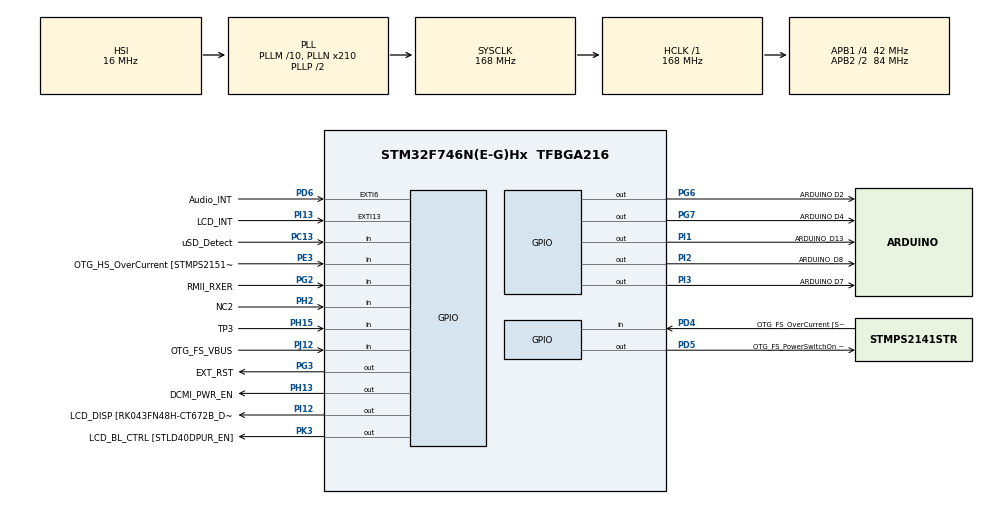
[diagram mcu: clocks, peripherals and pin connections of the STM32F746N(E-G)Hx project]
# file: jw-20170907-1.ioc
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Mcu.Family=STM32F7
Mcu.Name=STM32F746N(E-G)Hx
Mcu.Package=TFBGA216
NVIC.PriorityGroup=NVIC_PRIORITYGROUP_4
PA0/WKUP.GPIO_Label=ARDUINO A0
PA0/WKUP.GPIO_Mode=GPIO_MODE_ANALOG
PA0/WKUP.GPIO_PuPd=GPIO_NOPULL
PA0/WKUP.Signal=ADCx_IN0
PA1.GPIO_Label=RMII_REF_CLK [LAN8742A-CZ-TR_REFCLK0]
PA1.Signal=ETH_REF_CLK
PA10.GPIO_Label=OTG_FS_ID
PA10.Signal=USB_OTG_FS_ID
PA11.GPIO_Label=OTG_FS_N
PA11.Signal=USB_OTG_FS_DM
PA12.GPIO_Label=OTG_FS_P
PA12.Signal=USB_OTG_FS_DP
PA13.GPIO_Label=SWDIO
PA13.Signal=SYS_JTMS-SWDIO
PA14.GPIO_Label=SWCLK
PA14.Signal=SYS_JTCK-SWCLK
PA15.GPIO_Label=ARDUINO PWM/D9
PA15.GPIO_ModeDefaultPP=GPIO_MODE_AF_PP
PA15.GPIO_PuPd=GPIO_NOPULL
PA15.GPIO_Speed=GPIO_SPEED_FREQ_LOW
PA15.Signal=S_TIM2_CH1_ETR
PA2.GPIO_Label=RMII_MDIO [LAN8742A-CZ-TR_MDIO]
PA2.Signal=ETH_MDIO
PA3.GPIO_Label=ULPI_D0 [USB3320C-EZK_D0]
PA3.Signal=USB_OTG_HS_ULPI_D0
PA4.GPIO_Label=DCMI_HSYNC
PA4.Signal=DCMI_HSYNC
PA5.GPIO_Label=ULPI_CLK [USB3320C-EZK_CLKOUT]
PA5.Signal=USB_OTG_HS_ULPI_CK
PA6.Signal=DCMI_PIXCLK
PA7.GPIO_Label=RMII_CRS_DV [LAN8742A-CZ-TR_CRS_DV]
PA7.Signal=ETH_CRS_DV
PA8.GPIO_Label=ARDUINO PWM/D5
PA8.GPIO_ModeDefaultPP=GPIO_MODE_AF_PP
PA8.GPIO_PuPd=GPIO_NOPULL
PA8.GPIO_Speed=GPIO_SPEED_FREQ_LOW
PA8.Signal=S_TIM1_CH1
PB0.GPIO_Label=ULPI_D1 [USB3320C-EZK_D1]
PB0.Signal=USB_OTG_HS_ULPI_D1
PB1.GPIO_Label=ULPI_D2 [USB3320C-EZK_D2]
PB1.Signal=USB_OTG_HS_ULPI_D2
PB10.GPIO_Label=ULPI_D3 [USB3320C-EZK_D3]
PB10.Signal=USB_OTG_HS_ULPI_D3
PB11.GPIO_Label=ULPI_D4 [USB3320C-EZK_D4]
PB11.Signal=USB_OTG_HS_ULPI_D4
PB12.GPIO_Label=ULPI_D5 [USB3320C-EZK_D5]
PB12.Signal=USB_OTG_HS_ULPI_D5
PB13.GPIO_Label=ULPI_D6 [USB3320C-EZK_D6]
PB13.Signal=USB_OTG_HS_ULPI_D6
PB14.GPIO_Label=ARDUINO MISO/D12
PB14.GPIO_Mode=GPIO_MODE_AF_PP
PB14.GPIO_PuPd=GPIO_NOPULL
PB14.GPIO_Speed=GPIO_SPEED_FREQ_LOW
PB14.Signal=SPI2_MISO
PB15.GPIO_Label=ARDUINO MOSI/PWM/D11
PB15.GPIO_Mode=GPIO_MODE_AF_PP
PB15.GPIO_PuPd=GPIO_NOPULL
PB15.GPIO_Speed=GPIO_SPEED_FREQ_LOW
PB15.Signal=SPI2_MOSI
PB2.Signal=QUADSPI_CLK
PB3.GPIO_Label=SWO
PB3.Signal=SYS_JTDO-SWO
PB4.GPIO_Label=ARDUINO PWM/D3
PB4.GPIO_ModeDefaultPP=GPIO_MODE_AF_PP
PB4.GPIO_PuPd=GPIO_NOPULL
PB4.GPIO_Speed=GPIO_SPEED_FREQ_LOW
PB4.Signal=S_TIM3_CH1
PB5.GPIO_Label=ULPI_D7 [USB3320C-EZK_D7]
PB5.Signal=USB_OTG_HS_ULPI_D7
PB6.GPIO_Label=QSPI_NCS [N25Q128A13EF840E_S]
PB6.Signal=QUADSPI_BK1_NCS
PB7.GPIO_Label=VCP_RX [STM32F103CBT6_PA2]
PB7.GPIO_Mode=GPIO_MODE_AF_PP
PB7.GPIO_PuPd=GPIO_NOPULL
PB7.GPIO_Speed=GPIO_SPEED_FREQ_LOW
PB7.Signal=USART1_RX
PB8.GPIO_Label=ARDUINO SCL/D15
PB8.GPIO_Mode=GPIO_MODE_AF_OD
PB8.GPIO_PuPd=GPIO_NOPULL
PB8.GPIO_Speed=GPIO_SPEED_FREQ_LOW
PB8.Signal=I2C1_SCL
PB9.GPIO_Label=ARDUINO SDA/D14
PB9.GPIO_Mode=GPIO_MODE_AF_OD
PB9.GPIO_PuPd=GPIO_NOPULL
PB9.GPIO_Speed=GPIO_SPEED_FREQ_LOW
PB9.Signal=I2C1_SDA
PC0.GPIO_Label=ULPI_STP [USB3320C-EZK_STP]
PC0.Signal=USB_OTG_HS_ULPI_STP
PC1.GPIO_Label=RMII_MDC [LAN8742A-CZ-TR_MDC]
PC1.Signal=ETH_MDC
PC10.GPIO_Label=SDMMC_D2
PC10.Signal=SDMMC1_D2
PC11.GPIO_Label=SDMMC_D3
PC11.Signal=SDMMC1_D3
PC12.GPIO_Label=SDMMC_CK
PC12.Signal=SDMMC1_CK
PC13.GPIO_Label=uSD_Detect
PC13.Signal=GPIO_Input
PC14/OSC32_IN.GPIO_Label=RCC_OSC32_IN
PC14/OSC32_IN.Signal=RCC_OSC32_IN
PC15/OSC32_OUT.GPIO_Label=RCC_OSC32_OUT
PC15/OSC32_OUT.Signal=RCC_OSC32_OUT
PC2.GPIO_Label=ULPI_DIR [USB3320C-EZK_DIR]
PC2.Signal=USB_OTG_HS_ULPI_DIR
PC3.GPIO_Label=FMC_SDCKE0 [MT48LC4M32B2B5-6A_CKE]
PC3.Signal=FMC_SDCKE0
PC4.GPIO_Label=RMII_RXD0 [LAN8742A-CZ-TR_RXD0]
PC4.Signal=ETH_RXD0
PC5.GPIO_Label=RMII_RXD1 [LAN8742A-CZ-TR_RXD1]
PC5.Signal=ETH_RXD1
PC6.GPIO_Label=ARDUINO TX/D1
PC6.Signal=USART6_TX
PC7.GPIO_Label=ARDUINO RX/D0
PC7.Signal=USART6_RX
PC8.Signal=SDMMC1_D0
PC9.Signal=SDMMC1_D1
PD0.GPIO_Label=FMC_D2 [MT48LC4M32B2B5-6A_DQ2]
PD0.Signal=FMC_D2_DA2
PD1.GPIO_Label=FMC_D3 [MT48LC4M32B2B5-6A_DQ3]
PD1.Signal=FMC_D3_DA3
PD10.GPIO_Label=FMC_D15 [MT48LC4M32B2B5-6A_DQ15]
PD10.Signal=FMC_D15_DA15
PD11.GPIO_Label=QSPI_D0 [N25Q128A13EF840E_DQ0]
PD11.Signal=QUADSPI_BK1_IO0
PD12.GPIO_Label=QSPI_D1 [N25Q128A13EF840E_DQ1]
PD12.Signal=QUADSPI_BK1_IO1
PD13.GPIO_Label=QSPI_D3 [N25Q128A13EF840E_DQ3]
PD13.Signal=QUADSPI_BK1_IO3
PD14.GPIO_Label=FMC_D0 [MT48LC4M32B2B5-6A_DQ0]
PD14.Signal=FMC_D0_DA0
PD15.GPIO_Label=FMC_D1 [MT48LC4M32B2B5-6A_DQ1]
PD15.Signal=FMC_D1_DA1
PD2.GPIO_Label=SDMMC_D0
PD2.Signal=SDMMC1_CMD
PD3.GPIO_Label=DCMI_D5
PD3.Signal=DCMI_D5
PD4.GPIO_Label=OTG_FS_OverCurrent [STMPS2141STR_Fault]
PD4.Signal=GPIO_Input
PD5.GPIO_Label=OTG_FS_PowerSwitchOn [STMPS2141STR_EN]
PD5.PinState=GPIO_PIN_SET
PD5.Signal=GPIO_Output
PD6.GPIO_Label=Audio_INT
PD6.GPIO_ModeDefaultEXTI=GPIO_MODE_EVT_RISING
PD6.Signal=GPXTI6
PD7.GPIO_Label=SPDIF_RX0 [74LVC1G04SE_4]
PD7.Signal=SPDIFRX_IN0
PD8.GPIO_Label=FMC_D13 [MT48LC4M32B2B5-6A_DQ13]
PD8.Signal=FMC_D13_DA13
PD9.GPIO_Label=FMC_D14 [MT48LC4M32B2B5-6A_DQ14]
PD9.Signal=FMC_D14_DA14
PE0.GPIO_Label=FMC_NBL0 [MT48LC4M32B2B5-6A_DQM0]
PE0.Signal=FMC_NBL0
PE1.GPIO_Label=FMC_NBL1 [MT48LC4M32B2B5-6A_DQM1]
PE1.Signal=FMC_NBL1
PE10.GPIO_Label=FMC_D7 [MT48LC4M32B2B5-6A_DQ7]
PE10.Signal=FMC_D7_DA7
PE11.GPIO_Label=FMC_D8 [MT48LC4M32B2B5-6A_DQ8]
PE11.Signal=FMC_D8_DA8
PE12.GPIO_Label=FMC_D9 [MT48LC4M32B2B5-6A_DQ9]
PE12.Signal=FMC_D9_DA9
PE13.GPIO_Label=FMC_D10 [MT48LC4M32B2B5-6A_DQ10]
PE13.Signal=FMC_D10_DA10
PE14.GPIO_Label=FMC_D11 [MT48LC4M32B2B5-6A_DQ11]
PE14.Signal=FMC_D11_DA11
PE15.GPIO_Label=FMC_D12 [MT48LC4M32B2B5-6A_DQ12]
PE15.Signal=FMC_D12_DA12
PE2.GPIO_Label=QSPI_D2 [N25Q128A13EF840E_DQ2]
PE2.Signal=QUADSPI_BK1_IO2
PE3.GPIO_Label=OTG_HS_OverCurrent [STMPS2151STR_FAULT]
PE3.Signal=GPIO_Input
PE4.GPIO_Label=LCD_B0 [RK043FN48H-CT672B_B0]
PE4.Signal=LTDC_B0
PE5.GPIO_Label=DCMI_D6
PE5.Signal=DCMI_D6
PE6.GPIO_Label=DCMI_D7
PE6.Signal=DCMI_D7
PE7.GPIO_Label=FMC_D4 [MT48LC4M32B2B5-6A_DQ4]
PE7.Signal=FMC_D4_DA4
PE8.GPIO_Label=FMC_D5 [MT48LC4M32B2B5-6A_DQ5]
PE8.Signal=FMC_D5_DA5
PE9.GPIO_Label=FMC_D6 [MT48LC4M32B2B5-6A_DQ6]
PE9.Signal=FMC_D6_DA6
PF0.GPIO_Label=FMC_A0 [MT48LC4M32B2B5-6A_A0]
PF0.Signal=FMC_A0
PF1.GPIO_Label=FMC_A1 [MT48LC4M32B2B5-6A_A1]
PF1.Signal=FMC_A1
PF10.GPIO_Label=ARDUINO A1
PF10.GPIO_Mode=GPIO_MODE_ANALOG
PF10.GPIO_PuPd=GPIO_NOPULL
PF10.Signal=ADC3_IN8
PF11.GPIO_Label=FMC_SDNRAS [MT48LC4M32B2B5-6A_RAS]
PF11.Signal=FMC_SDNRAS
PF12.GPIO_Label=FMC_A6 [MT48LC4M32B2B5-6A_A6]
PF12.Signal=FMC_A6
PF13.GPIO_Label=FMC_A7 [MT48LC4M32B2B5-6A_A7]
PF13.Signal=FMC_A7
PF14.GPIO_Label=FMC_A8 [MT48LC4M32B2B5-6A_A8]
PF14.Signal=FMC_A8
PF15.GPIO_Label=FMC_A9 [MT48LC4M32B2B5-6A_A9]
PF15.Signal=FMC_A9
PF2.GPIO_Label=FMC_A2 [MT48LC4M32B2B5-6A_A2]
PF2.Signal=FMC_A2
PF3.GPIO_Label=FMC_A3 [MT48LC4M32B2B5-6A_A3]
PF3.Signal=FMC_A3
PF4.GPIO_Label=FMC_A4 [MT48LC4M32B2B5-6A_A4]
PF4.Signal=FMC_A4
PF5.GPIO_Label=FMC_A5 [MT48LC4M32B2B5-6A_A5]
PF5.Signal=FMC_A5
PF6.GPIO_Label=ARDUINO A5
PF6.GPIO_Mode=GPIO_MODE_ANALOG
PF6.GPIO_PuPd=GPIO_NOPULL
PF6.Signal=ADC3_IN4
PF7.GPIO_Label=ARDUINO A4
PF7.GPIO_Mode=GPIO_MODE_ANALOG
PF7.GPIO_PuPd=GPIO_NOPULL
PF7.Signal=ADC3_IN5
PF8.GPIO_Label=ARDUINO A3
PF8.GPIO_Mode=GPIO_MODE_ANALOG
PF8.GPIO_PuPd=GPIO_NOPULL
PF8.Signal=ADC3_IN6
PF9.GPIO_Label=ARDUINO A2
PF9.GPIO_Mode=GPIO_MODE_ANALOG
PF9.GPIO_PuPd=GPIO_NOPULL
PF9.Signal=ADC3_IN7
PG0.GPIO_Label=FMC_A10 [MT48LC4M32B2B5-6A_A10]
PG0.Signal=FMC_A10
PG1.GPIO_Label=FMC_A11 [MT48LC4M32B2B5-6A_A11]
PG1.Signal=FMC_A11
PG10.GPIO_Label=SAI2_SDB [WM8994ECS/R_ADCDAT1]
PG10.Signal=SAI2_SD_B
PG11.GPIO_Label=RMII_TX_EN [LAN8742A-CZ-TR_TXEN]
PG11.Signal=ETH_TX_EN
PG12.GPIO_Label=LCD_B4 [RK043FN48H-CT672B_B4]
PG12.Signal=LTDC_B4
PG13.GPIO_Label=RMII_TXD0 [LAN8742A-CZ-TR_TXD0]
PG13.Signal=ETH_TXD0
PG14.GPIO_Label=RMII_TXD1 [LAN8742A-CZ-TR_TXD1]
PG14.Signal=ETH_TXD1
PG15.GPIO_Label=FMC_SDNCAS [MT48LC4M32B2B5-6A_CAS]
PG15.Signal=FMC_SDNCAS
PG2.GPIO_Label=RMII_RXER
PG2.Signal=GPIO_Input
PG3.GPIO_Label=EXT_RST
PG3.Signal=GPIO_Output
PG4.GPIO_Label=FMC_BA0 [MT48LC4M32B2B5-6A_BA0]
PG4.Signal=FMC_A14_BA0
PG5.GPIO_Label=FMC_BA1 [MT48LC4M32B2B5-6A_BA1]
PG5.Signal=FMC_A15_BA1
PG6.GPIO_Label=ARDUINO D2
PG6.Signal=GPIO_Output
PG7.GPIO_Label=ARDUINO D4
PG7.Signal=GPIO_Output
PG8.GPIO_Label=FMC_SDCLK [MT48LC4M32B2B5-6A_CLK]
PG8.Signal=FMC_SDCLK
PG9.GPIO_Label=DCMI_VSYNC
PG9.Signal=DCMI_VSYNC
PH0/OSC_IN.GPIO_Label=OSC_25M [NZ2520SB-25.00M_OUT]
PH0/OSC_IN.Signal=RCC_OSC_IN
PH1/OSC_OUT.Signal=RCC_OSC_OUT
PH10.GPIO_Label=DCMI_D1
PH10.Signal=DCMI_D1
PH11.GPIO_Label=DCMI_D2
PH11.Signal=DCMI_D2
PH12.GPIO_Label=DCMI_D3
PH12.Signal=DCMI_D3
PH13.GPIO_Label=DCMI_PWR_EN
PH13.Signal=GPIO_Output
PH14.GPIO_Label=DCMI_D4
PH14.Signal=DCMI_D4
PH15.GPIO_Label=TP3
PH15.Signal=GPIO_Input
PH2.GPIO_Label=NC2
PH2.Signal=GPIO_Input
PH3.GPIO_Label=FMC_SDNE0 [MT48LC4M32B2B5-6A_CS]
PH3.Signal=FMC_SDNE0
PH4.GPIO_Label=ULPI_NXT [USB3320C-EZK_NXT]
PH4.Signal=USB_OTG_HS_ULPI_NXT
PH5.GPIO_Label=FMC_SDNME [MT48LC4M32B2B5-6A_WE]
PH5.Signal=FMC_SDNWE
PH6.GPIO_Label=ARDUINO PWM/D6
PH6.Signal=S_TIM12_CH1
PH7.GPIO_Label=LCD_SCL [RK043FN48H-CT672B_SCL]
PH7.Signal=I2C3_SCL
PH8.GPIO_Label=LCD_SDA [RK043FN48H-CT672B_SDA]
PH8.Signal=I2C3_SDA
PH9.GPIO_Label=DCMI_D0
PH9.Signal=DCMI_D0
PI0.GPIO_Label=ARDUINO PWM/CS/D10
PI0.GPIO_ModeDefaultPP=GPIO_MODE_AF_PP
PI0.GPIO_PuPd=GPIO_NOPULL
PI0.GPIO_Speed=GPIO_SPEED_FREQ_LOW
PI0.Signal=S_TIM5_CH4
PI1.GPIO_Label=ARDUINO_D13
PI1.Signal=GPIO_Output
PI10.GPIO_Label=LCD_HSYNC [RK043FN48H-CT672B_HSYNC]
PI10.Signal=LTDC_HSYNC
PI12.GPIO_Label=LCD_DISP [RK043FN48H-CT672B_DISP] 
PI12.Signal=GPIO_Output
PI13.GPIO_Label=LCD_INT
PI13.GPIO_ModeDefaultEXTI=GPIO_MODE_EVT_RISING
PI13.Signal=GPXTI13
PI14.GPIO_Label=LCD_CLK [RK043FN48H-CT672B_CLK]
PI14.Signal=LTDC_CLK
PI15.GPIO_Label=LCD_R0 [RK043FN48H-CT672B_R0]
PI15.Signal=LTDC_R0
PI2.GPIO_Label=ARDUINO_D8
PI2.Signal=GPIO_Output
PI3.GPIO_Label=ARDUINO D7
PI3.Signal=GPIO_Output
PI4.GPIO_Label=SAI2_MCLKA [WM8994ECS/R_MCLK1]
PI4.Signal=SAI2_MCLK_A
PI5.GPIO_Label=SAI2_SCKA [WM8994ECS/R_BCLK1]
PI5.Signal=SAI2_SCK_A
PI6.GPIO_Label=SAI2_SDA [WM8994ECS/R_DACDAT1]
PI6.Signal=SAI2_SD_A
PI7.GPIO_Label=SAI2_FSA [WM8994ECS/R_LRCLK1]
PI7.Signal=SAI2_FS_A
PI8.GPIO_Label=NC1 [TP2]
PI8.Signal=RTC_TS
PI9.GPIO_Label=LCD_VSYNC [RK043FN48H-CT672B_VSYNC]
PI9.Signal=LTDC_VSYNC
PJ0.GPIO_Label=LCD_R1 [RK043FN48H-CT672B_R1]
PJ0.Signal=LTDC_R1
PJ1.GPIO_Label=LCD_R2 [RK043FN48H-CT672B_R2]
PJ1.Signal=LTDC_R2
PJ10.GPIO_Label=LCD_G3 [RK043FN48H-CT672B_G3]
PJ10.Signal=LTDC_G3
PJ11.GPIO_Label=LCD_G4 [RK043FN48H-CT672B_G4]
PJ11.Signal=LTDC_G4
PJ12.GPIO_Label=OTG_FS_VBUS
PJ12.Signal=GPIO_Input
PJ13.GPIO_Label=LCD_B1 [RK043FN48H-CT672B_B1]
PJ13.Signal=LTDC_B1
PJ14.GPIO_Label=LCD_B2 [RK043FN48H-CT672B_B2]
PJ14.Signal=LTDC_B2
PJ15.GPIO_Label=LCD_B3 [RK043FN48H-CT672B_B3]
PJ15.Signal=LTDC_B3
PJ2.GPIO_Label=LCD_R3 [RK043FN48H-CT672B_R3]
PJ2.Signal=LTDC_R3
PJ3.GPIO_Label=LCD_R4 [RK043FN48H-CT672B_R4]
PJ3.Signal=LTDC_R4
PJ4.GPIO_Label=LCD_R5 [RK043FN48H-CT672B_R5]
PJ4.Signal=LTDC_R5
PJ5.GPIO_Label=LCD_R6 [RK043FN48H-CT672B_R6]
PJ5.Signal=LTDC_R6
PJ6.GPIO_Label=LCD_R7 [RK043FN48H-CT672B_R7]
PJ6.Signal=LTDC_R7
PJ7.GPIO_Label=LCD_G0 [RK043FN48H-CT672B_G0]
PJ7.Signal=LTDC_G0
PJ8.GPIO_Label=LCD_G1 [RK043FN48H-CT672B_G1]
PJ8.Signal=LTDC_G1
PJ9.GPIO_Label=LCD_G2 [RK043FN48H-CT672B_G2]
PJ9.Signal=LTDC_G2
PK0.GPIO_Label=LCD_G5 [RK043FN48H-CT672B_G5]
PK0.Signal=LTDC_G5
PK1.GPIO_Label=LCD_G6 [RK043FN48H-CT672B_G6]
PK1.Signal=LTDC_G6
PK2.GPIO_Label=LCD_G7 [RK043FN48H-CT672B_G7]
PK2.Signal=LTDC_G7
PK3.GPIO_Label=LCD_BL_CTRL [STLD40DPUR_EN]
PK3.Signal=GPIO_Output
PK4.GPIO_Label=LCD_B5 [RK043FN48H-CT672B_B5]
PK4.Signal=LTDC_B5
PK5.GPIO_Label=LCD_B6 [RK043FN48H-CT672B_B6]
PK5.Signal=LTDC_B6
PK6.GPIO_Label=LCD_B7 [RK043FN48H-CT672B_B7]
PK6.Signal=LTDC_B7
PK7.GPIO_Label=LCD_DE [RK043FN48H-CT672B_DE]
PK7.Signal=LTDC_DE
ProjectManager.HeapSize=0x200
ProjectManager.StackSize=0x400
ProjectManager.TargetToolchain=EWARM
RCC.AHBFreq_Value=168000000
RCC.APB1CLKDivider=RCC_HCLK_DIV4
RCC.APB1Freq_Value=42000000
RCC.APB1TimFreq_Value=84000000
RCC.APB2CLKDivider=RCC_HCLK_DIV2
RCC.APB2Freq_Value=84000000
RCC.APB2TimFreq_Value=168000000
RCC.CortexFreq_Value=168000000
RCC.HCLKFreq_Value=168000000
RCC.HSE_VALUE=25000000
RCC.HSI_VALUE=16000000
RCC.LSE_VALUE=32768
RCC.PLLM=10
RCC.PLLN=210
RCC.PLLSourceVirtual=RCC_PLLSOURCE_HSI
RCC.SYSCLKFreq_VALUE=168000000
RCC.SYSCLKSource=RCC_SYSCLKSOURCE_PLLCLK
RCC.USBFreq_Value=168000000
RCC.VCOOutputFreq_Value=336000000
SH.ADCx_IN0.0=ADC3_IN0
SH.FMC_A0.0=FMC_A0
SH.FMC_A1.0=FMC_A1
SH.FMC_A10.0=FMC_A10
SH.FMC_A11.0=FMC_A11
SH.FMC_A14_BA0.0=FMC_BA0
SH.FMC_A15_BA1.0=FMC_BA1
SH.FMC_A2.0=FMC_A2
SH.FMC_A3.0=FMC_A3
SH.FMC_A4.0=FMC_A4
SH.FMC_A5.0=FMC_A5
SH.FMC_A6.0=FMC_A6
SH.FMC_A7.0=FMC_A7
SH.FMC_A8.0=FMC_A8
SH.FMC_A9.0=FMC_A9
SH.FMC_D0_DA0.0=FMC_D0
SH.FMC_D10_DA10.0=FMC_D10
SH.FMC_D11_DA11.0=FMC_D11
SH.FMC_D12_DA12.0=FMC_D12
SH.FMC_D13_DA13.0=FMC_D13
SH.FMC_D14_DA14.0=FMC_D14
SH.FMC_D15_DA15.0=FMC_D15
SH.FMC_D1_DA1.0=FMC_D1
SH.FMC_D2_DA2.0=FMC_D2
SH.FMC_D3_DA3.0=FMC_D3
SH.FMC_D4_DA4.0=FMC_D4
SH.FMC_D5_DA5.0=FMC_D5
SH.FMC_D6_DA6.0=FMC_D6
SH.FMC_D7_DA7.0=FMC_D7
SH.FMC_D8_DA8.0=FMC_D8
SH.FMC_D9_DA9.0=FMC_D9
SH.FMC_NBL0.0=FMC_NBL0
SH.FMC_NBL1.0=FMC_NBL1
SH.FMC_SDCLK.0=FMC_SDCLK
SH.FMC_SDNCAS.0=FMC_SDNCAS
SH.FMC_SDNRAS.0=FMC_SDNRAS
SH.FMC_SDNWE.0=FMC_SDNWE
SH.S_TIM12_CH1.0=TIM12_CH1
SH.S_TIM1_CH1.0=TIM1_CH1
SH.S_TIM2_CH1_ETR.0=TIM2_CH1
SH.S_TIM3_CH1.0=TIM3_CH1
SH.S_TIM5_CH4.0=TIM5_CH4
board=STM32F746G-DISCO

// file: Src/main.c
/**
  ******************************************************************************
  * File Name          : main.c
  * Description        : Main program body
  ******************************************************************************
  ** This notice applies to any and all portions of this file
  * that are not between comment pairs USER CODE BEGIN and
  * USER CODE END. Other portions of this file, whether
  * inserted by the user or by software development tools
  * are owned by their respective copyright owners.
  *
  * COPYRIGHT(c) 2017 STMicroelectronics
  *
  * Redistribution and use in source and binary forms, with or without modification,
  * are permitted provided that the following conditions are met:
  *   1. Redistributions of source code must retain the above copyright notice,
  *      this list of conditions and the following disclaimer.
  *   2. Redistributions in binary form must reproduce the above copyright notice,
  *      this list of conditions and the following disclaimer in the documentation
  *      and/or other materials provided with the distribution.
  *   3. Neither the name of STMicroelectronics nor the names of its contributors
  *      may be used to endorse or promote products derived from this software
  *      without specific prior written permission.
  *
  * THIS SOFTWARE IS PROVIDED BY THE COPYRIGHT HOLDERS AND CONTRIBUTORS "AS IS"
  * AND ANY EXPRESS OR IMPLIED WARRANTIES, INCLUDING, BUT NOT LIMITED TO, THE
  * IMPLIED WARRANTIES OF MERCHANTABILITY AND FITNESS FOR A PARTICULAR PURPOSE ARE
  * DISCLAIMED. IN NO EVENT SHALL THE COPYRIGHT HOLDER OR CONTRIBUTORS BE LIABLE
  * FOR ANY DIRECT, INDIRECT, INCIDENTAL, SPECIAL, EXEMPLARY, OR CONSEQUENTIAL
  * DAMAGES (INCLUDING, BUT NOT LIMITED TO, PROCUREMENT OF SUBSTITUTE GOODS OR
  * SERVICES; LOSS OF USE, DATA, OR PROFITS; OR BUSINESS INTERRUPTION) HOWEVER
  * CAUSED AND ON ANY THEORY OF LIABILITY, WHETHER IN CONTRACT, STRICT LIABILITY,
  * OR TORT (INCLUDING NEGLIGENCE OR OTHERWISE) ARISING IN ANY WAY OUT OF THE USE
  * OF THIS SOFTWARE, EVEN IF ADVISED OF THE POSSIBILITY OF SUCH DAMAGE.
  *
  ******************************************************************************
  */
#include "main.h"
#include "stm32f7xx_hal.h"
#include "main_FSM.h"

/*
This code Written By DDubi(jw8704@gmail.com).
Date : 2017.09.18
Coaching from Firmware enginner's talk chatroom's master
*/

//This Conidtion is optional. (written by DDubi(kim jinwoo)
#define USING_DELAY_VER

//Only one condition must be specified.(written by DDubi(kim jinwoo)
//#define USING_QUEUE
#define USING_FLAG

//CAUTION!!! Do not Remove or Modify (Written By DDubi(kim jinwoo)---->
#if defined(USING_FLAG) && defined (USING_QUEUE)
CAUTION! Both conditions can not exist at the same time.
#endif
#if !defined(USING_FLAG) && !defined (USING_QUEUE)
CAUTION! One of the two conditions must be specified.
#endif
//<------Caution!! Do not Remove or Modify(Written By DDubi(kim jinwoo)

/* USER CODE BEGIN PV */
/* Private variables ---------------------------------------------------------*/

/* USER CODE END PV */

void SystemClock_Config(void);
static void MX_GPIO_Init(void);
typedef int element;

extern void enqueue(int *rear,element item);
extern int isEmpty(int *front,int rear);
extern element dequeue(int *front,int rear);
extern void deleteitem(int *front,int rear);
extern element peek(int front,int rear);

/* USER CODE BEGIN PFP */
/* Private function prototypes -----------------------------------------------*/

/* USER CODE END PFP */

int ledstate=0;

#ifdef USING_FLAG
int updateEvent=0;
#endif

 //FSM_EVT e;
 //FSM     f;
  FSM_EVT e;
 FSM     f;

 int front = -1;
 int rear = -1;

void HAL_GPIO_EXTI_Callback(uint16_t GPIO_Pin)
{

 /*
  if(ledstate==0)
  {
   InitStateMachine(
        &f,                  // 초기화할 FSM 개체(개수만큼 생성 초기화해준다)
        InitMainFSM(&f),     // MainFSM 초기화함수(FSM 마다 만들어 준다) : 상태테이블 리턴
        _MOVEMAN_MAX_EVT,    // 이벤트 개수
        _MOVEMAN_MAX_STATE   // STATE  개수
    );
   ledstate=9;
  }*/
  //else
 // {
  // __HAL_GPIO_EXTI_CLEAR_IT(GPIO_PIN_11);
 // UNUSED(GPIO_PIN_11);
 // asm("NOP");
//
                if(GetState(f)==_MOVEMAN_LEVEL_1)
                {
                  asm("NOP");
                    e.EVT = _MOVEMAN_GO_UP;   //DoEvent(&f, e);
#ifdef USING_QUEUE
                    enqueue(&rear,e.EVT);
#endif
                     asm("NOP");
                  //  asm("NOP");
                   // UNUSED(GPIO_PIN_11);
#ifdef USING_FLAG
                     updateEvent=1;
#endif
                }

                else if(GetState(f)==_MOVEMAN_LEVEL_2)
               {
                 asm("NOP");

                 e.EVT = _MOVEMAN_GO_DOWN; //DoEvent(&f, e);
#ifdef USING_QUEUE
                 enqueue(&rear,e.EVT);
#endif
                  asm("NOP");
#ifdef USING_FLAG
                  updateEvent=1;
#endif
               }
 // }
               //  asm("NOP");
            // UNUSED(GPIO_PIN_11);
              // }
           //asm("NOP");

  //HAL_GPIO_TogglePin(LCD_BK_CTRL_GPIO_Port, LCD_BK_CTRL_Pin);

  /*
  if(ledstate==0)
                {
                HAL_GPIO_WritePin(GPIOI,ARDUINO_D7_Pin,GPIO_PIN_RESET);
                HAL_GPIO_WritePin(GPIOI,ARDUINO_D8_Pin,GPIO_PIN_RESET);
                HAL_GPIO_TogglePin(GPIOI,ARDUINO_D7_Pin);
                ledstate=1;
                //HAL_Delay(180);
                printf("test\n");
                }
                else if(ledstate==1)
                {
                HAL_GPIO_WritePin(GPIOI,ARDUINO_D7_Pin,GPIO_PIN_RESET);
                HAL_GPIO_WritePin(GPIOI,ARDUINO_D8_Pin,GPIO_PIN_RESET);
                HAL_GPIO_TogglePin(GPIOI,ARDUINO_D8_Pin);
                ledstate=0;
                //HAL_Delay(180);
                }*/
  //UNUSED(GPIO_PIN_11);
          // __HAL_GPIO_EXTI_CLEAR_IT(GPIO_PIN_11);
}

int main(void)
{

 //FSM_EVT e;
 //  FSM     f;

  /* USER CODE BEGIN 1 */

    // StateMachine 초기화

    InitStateMachine(
        &f,                  // 초기화할 FSM 개체(개수만큼 생성 초기화해준다)
        InitMainFSM(&f),     // MainFSM 초기화함수(FSM 마다 만들어 준다) : 상태테이블 리턴
        _MOVEMAN_MAX_EVT,    // 이벤트 개수
        _MOVEMAN_MAX_STATE   // STATE  개수
    );

  /* USER CODE END 1 */

  /* MCU Configuration----------------------------------------------------------*/

  /* Reset of all peripherals, Initializes the Flash interface and the Systick. */
  HAL_Init();

  /* Configure the system clock */
  SystemClock_Config();

  /* Initialize all configured peripherals */
  MX_GPIO_Init();

  /* Infinite loop */
  /* USER CODE BEGIN WHILE */

  //RCC->AHB1ENR |= 0x00000100;  // GPIOI clock enable
  //GPIOI->MODER = 0x00000008;   // PI1 (LED) output

//  uint8_t sw_in,sw_in_old,f_test=0;
 // sw_in = sw_in_old = HAL_GPIO_ReadPin(SW_IN_GPIO_Port,SW_IN_Pin);

 //int ledstate;

 //ledstate=0;
  //MX_USART1_UART_Init();

 while (1)
  {
  /* USER CODE END WHILE */
//delay(1000);
#ifdef USING_DELAY_VER
  HAL_Delay(1000);
#endif

#ifdef USING_QUEUE
  if(front!=rear)
#endif
#ifdef USING_FLAG
   if(updateEvent)
#endif
    {
#ifdef USING_QUEUE
    if(peek(front,rear) == _MOVEMAN_GO_UP)
#endif
#ifdef USING_FLAG
      if(e.EVT == _MOVEMAN_GO_UP)
#endif
                {
                  asm("NOP");
                    //e.EVT = _MOVEMAN_GO_UP;
                  DoEvent(&f, e);
                     asm("NOP");
                  //  asm("NOP");
                   // UNUSED(GPIO_PIN_11);
                }
#ifdef USING_QUEUE
    else if(peek(front,rear) == _MOVEMAN_GO_DOWN)
#endif
#ifdef USING_FLAG
     else if(e.EVT == _MOVEMAN_GO_DOWN)
#endif
               {
                 asm("NOP");

                 //e.EVT = _MOVEMAN_GO_DOWN;

                 DoEvent(&f, e);
                  asm("NOP");
               }
#ifdef USING_QUEUE
     dequeue(&front,rear);
#endif

#ifdef USING_FLAG
     updateEvent=0;
#endif
    }

  /* USER CODE BEGIN 3 */
 // HAL_GPIO_TogglePin(GPIOI,ARDUINO_D8_Pin);
  //HAL_Delay(1000);

        //    if (GPIOI->IDR & 0x0800) // Input state of PI11 (switch)
       //     {
                     //GPIOI->BSRR = 0x00000002;  // Set PI1
                // HAL_GPIO_TogglePin(GPIOI,ARDUINO_D8_Pin);
                // HAL_GPIO_TogglePin(GPIOI,ARDUINO_D8_Pin);
               /*
              if(GetState(f)==_MOVEMAN_LEVEL_1)
                {
                    e.EVT = _MOVEMAN_GO_UP;    DoEvent(&f, e);
                }
                else if(GetState(f)==_MOVEMAN_LEVEL_2)
               {
                    e.EVT = _MOVEMAN_GO_DOWN;  DoEvent(&f, e);
               }

                 */
                 //HAL_Delay(1000);
           //  }
              /*
              else
              {
               // HAL_GPIO_TogglePin(GPIOI,ARDUINO_D7_Pin);
                HAL_GPIO_WritePin(GPIOI,ARDUINO_D7_Pin,GPIO_PIN_RESET);
                 HAL_GPIO_TogglePin(GPIOI,ARDUINO_D8_Pin);
                 //HAL_Delay(1000);
               // HAL_GPIO_TogglePin(GPIOI,ARDUINO_D8_Pin);
                     //GPIOI->BSRR = 0x00020000;  // Reset PI1
              }
              */
  }
}
  /* USER CODE END 3 */

/** System Clock Configuration
*/
void SystemClock_Config(void)
{

  RCC_OscInitTypeDef RCC_OscInitStruct;
  RCC_ClkInitTypeDef RCC_ClkInitStruct;

    /**Configure the main internal regulator output voltage
    */
  __HAL_RCC_PWR_CLK_ENABLE();

  __HAL_PWR_VOLTAGESCALING_CONFIG(PWR_REGULATOR_VOLTAGE_SCALE2);

    /**Initializes the CPU, AHB and APB busses clocks
    */
  RCC_OscInitStruct.OscillatorType = RCC_OSCILLATORTYPE_HSI;
  RCC_OscInitStruct.HSIState = RCC_HSI_ON;
  RCC_OscInitStruct.HSICalibrationValue = 16;
  RCC_OscInitStruct.PLL.PLLState = RCC_PLL_ON;
  RCC_OscInitStruct.PLL.PLLSource = RCC_PLLSOURCE_HSI;
  RCC_OscInitStruct.PLL.PLLM = 10;
  RCC_OscInitStruct.PLL.PLLN = 210;
  RCC_OscInitStruct.PLL.PLLP = RCC_PLLP_DIV2;
  RCC_OscInitStruct.PLL.PLLQ = 2;
  if (HAL_RCC_OscConfig(&RCC_OscInitStruct) != HAL_OK)
  {
    _Error_Handler(__FILE__, __LINE__);
  }

    /**Initializes the CPU, AHB and APB busses clocks
    */
  RCC_ClkInitStruct.ClockType = RCC_CLOCKTYPE_HCLK|RCC_CLOCKTYPE_SYSCLK
                              |RCC_CLOCKTYPE_PCLK1|RCC_CLOCKTYPE_PCLK2;
  RCC_ClkInitStruct.SYSCLKSource = RCC_SYSCLKSOURCE_PLLCLK;
  RCC_ClkInitStruct.AHBCLKDivider = RCC_SYSCLK_DIV1;
  RCC_ClkInitStruct.APB1CLKDivider = RCC_HCLK_DIV4;
  RCC_ClkInitStruct.APB2CLKDivider = RCC_HCLK_DIV2;

  if (HAL_RCC_ClockConfig(&RCC_ClkInitStruct, FLASH_LATENCY_5) != HAL_OK)
  {
    _Error_Handler(__FILE__, __LINE__);
  }

    /**Configure the Systick interrupt time
    */
  HAL_SYSTICK_Config(HAL_RCC_GetHCLKFreq()/1000);

    /**Configure the Systick
    */
  HAL_SYSTICK_CLKSourceConfig(SYSTICK_CLKSOURCE_HCLK);

  /* SysTick_IRQn interrupt configuration */
  HAL_NVIC_SetPriority(SysTick_IRQn, 0, 0);
}

/** Configure pins
     PE4   ------> LTDC_B0
     PE2   ------> QUADSPI_BK1_IO2
     PG14   ------> ETH_TXD1
     PE1   ------> FMC_NBL1
     PE0   ------> FMC_NBL0
     PB8   ------> I2C1_SCL
     PB5   ------> USB_OTG_HS_ULPI_D7
     PB4   ------> S_TIM3_CH1
     PD7   ------> SPDIFRX_IN0
     PC12   ------> SDMMC1_CK
     PA15   ------> S_TIM2_CH1_ETR
     PE5   ------> DCMI_D6
     PE6   ------> DCMI_D7
     PG13   ------> ETH_TXD0
     PB9   ------> I2C1_SDA
     PB7   ------> USART1_RX
     PB6   ------> QUADSPI_BK1_NCS
     PG15   ------> FMC_SDNCAS
     PG11   ------> ETH_TX_EN
     PJ13   ------> LTDC_B1
     PD0   ------> FMC_D2_DA2
     PC11   ------> SDMMC1_D3
     PC10   ------> SDMMC1_D2
     PA12   ------> USB_OTG_FS_DP
     PI4   ------> SAI2_MCLK_A
     PK7   ------> LTDC_DE
     PK6   ------> LTDC_B7
     PK5   ------> LTDC_B6
     PG12   ------> LTDC_B4
     PG10   ------> SAI2_SD_B
     PJ14   ------> LTDC_B2
     PD3   ------> DCMI_D5
     PD1   ------> FMC_D3_DA3
     PA11   ------> USB_OTG_FS_DM
     PF0   ------> FMC_A0
     PI5   ------> SAI2_SCK_A
     PI7   ------> SAI2_FS_A
     PI10   ------> LTDC_HSYNC
     PI6   ------> SAI2_SD_A
     PK4   ------> LTDC_B5
     PG9   ------> DCMI_VSYNC
     PJ15   ------> LTDC_B3
     PD2   ------> SDMMC1_CMD
     PA10   ------> USB_OTG_FS_ID
     PF1   ------> FMC_A1
     PI9   ------> LTDC_VSYNC
     PH14   ------> DCMI_D4
     PI0   ------> S_TIM5_CH4
     PK1   ------> LTDC_G6
     PK2   ------> LTDC_G7
     PC9   ------> SDMMC1_D1
     PA8   ------> S_TIM1_CH1
     PF2   ------> FMC_A2
     PI15   ------> LTDC_R0
     PJ11   ------> LTDC_G4
     PK0   ------> LTDC_G5
     PC8   ------> SDMMC1_D0
     PC7   ------> USART6_RX
     PF3   ------> FMC_A3
     PI14   ------> LTDC_CLK
     PH4   ------> USB_OTG_HS_ULPI_NXT
     PJ8   ------> LTDC_G1
     PJ10   ------> LTDC_G3
     PG8   ------> FMC_SDCLK
     PC6   ------> USART6_TX
     PF4   ------> FMC_A4
     PH5   ------> FMC_SDNWE
     PH3   ------> FMC_SDNE0
     PJ7   ------> LTDC_G0
     PJ9   ------> LTDC_G2
     PF7   ------> ADC3_IN5
     PF6   ------> ADC3_IN4
     PF5   ------> FMC_A5
     PJ6   ------> LTDC_R7
     PD15   ------> FMC_D1_DA1
     PB13   ------> USB_OTG_HS_ULPI_D6
     PD10   ------> FMC_D15_DA15
     PF10   ------> ADC3_IN8
     PF9   ------> ADC3_IN7
     PF8   ------> ADC3_IN6
     PC3   ------> FMC_SDCKE0
     PD14   ------> FMC_D0_DA0
     PB12   ------> USB_OTG_HS_ULPI_D5
     PD9   ------> FMC_D14_DA14
     PD8   ------> FMC_D13_DA13
     PC0   ------> USB_OTG_HS_ULPI_STP
     PC1   ------> ETH_MDC
     PC2   ------> USB_OTG_HS_ULPI_DIR
     PB2   ------> QUADSPI_CLK
     PF12   ------> FMC_A6
     PG1   ------> FMC_A11
     PF15   ------> FMC_A9
     PJ4   ------> LTDC_R5
     PD12   ------> QUADSPI_BK1_IO1
     PD13   ------> QUADSPI_BK1_IO3
     PJ5   ------> LTDC_R6
     PH12   ------> DCMI_D3
     PA1   ------> ETH_REF_CLK
     PA0/WKUP   ------> ADCx_IN0
     PA4   ------> DCMI_HSYNC
     PC4   ------> ETH_RXD0
     PF13   ------> FMC_A7
     PG0   ------> FMC_A10
     PJ3   ------> LTDC_R4
     PE8   ------> FMC_D5_DA5
     PD11   ------> QUADSPI_BK1_IO0
     PG5   ------> FMC_A15_BA1
     PG4   ------> FMC_A14_BA0
     PH7   ------> I2C3_SCL
     PH9   ------> DCMI_D0
     PH11   ------> DCMI_D2
     PA2   ------> ETH_MDIO
     PA6   ------> DCMI_PIXCLK
     PA5   ------> USB_OTG_HS_ULPI_CK
     PC5   ------> ETH_RXD1
     PF14   ------> FMC_A8
     PJ2   ------> LTDC_R3
     PF11   ------> FMC_SDNRAS
     PE9   ------> FMC_D6_DA6
     PE11   ------> FMC_D8_DA8
     PE14   ------> FMC_D11_DA11
     PB10   ------> USB_OTG_HS_ULPI_D3
     PH6   ------> S_TIM12_CH1
     PH8   ------> I2C3_SDA
     PH10   ------> DCMI_D1
     PA3   ------> USB_OTG_HS_ULPI_D0
     PA7   ------> ETH_CRS_DV
     PB1   ------> USB_OTG_HS_ULPI_D2
     PB0   ------> USB_OTG_HS_ULPI_D1
     PJ0   ------> LTDC_R1
     PJ1   ------> LTDC_R2
     PE7   ------> FMC_D4_DA4
     PE10   ------> FMC_D7_DA7
     PE12   ------> FMC_D9_DA9
     PE15   ------> FMC_D12_DA12
     PE13   ------> FMC_D10_DA10
     PB11   ------> USB_OTG_HS_ULPI_D4
     PB14   ------> SPI2_MISO
     PB15   ------> SPI2_MOSI
*/
static void MX_GPIO_Init(void)
{

  GPIO_InitTypeDef GPIO_InitStruct;

  /* GPIO Ports Clock Enable */
  __HAL_RCC_GPIOE_CLK_ENABLE();
  __HAL_RCC_GPIOG_CLK_ENABLE();
  __HAL_RCC_GPIOB_CLK_ENABLE();
  __HAL_RCC_GPIOD_CLK_ENABLE();
  __HAL_RCC_GPIOC_CLK_ENABLE();
  __HAL_RCC_GPIOA_CLK_ENABLE();
  __HAL_RCC_GPIOJ_CLK_ENABLE();
  __HAL_RCC_GPIOI_CLK_ENABLE();
  __HAL_RCC_GPIOK_CLK_ENABLE();
  __HAL_RCC_GPIOF_CLK_ENABLE();
  __HAL_RCC_GPIOH_CLK_ENABLE();

  /*Configure GPIO pin Output Level */
  HAL_GPIO_WritePin(OTG_FS_PowerSwitchOn_GPIO_Port, OTG_FS_PowerSwitchOn_Pin, GPIO_PIN_SET);

  /*Configure GPIO pin Output Level */
  HAL_GPIO_WritePin(GPIOI, ARDUINO_D7_Pin|ARDUINO_D8_Pin|LCD_DISP_Pin, GPIO_PIN_RESET);

  /*Configure GPIO pin Output Level */
  HAL_GPIO_WritePin(LCD_BL_CTRL_GPIO_Port, LCD_BL_CTRL_Pin, GPIO_PIN_RESET);

  /*Configure GPIO pin Output Level */
  HAL_GPIO_WritePin(DCMI_PWR_EN_GPIO_Port, DCMI_PWR_EN_Pin, GPIO_PIN_RESET);

  /*Configure GPIO pin Output Level */
  HAL_GPIO_WritePin(GPIOG, ARDUINO_D4_Pin|EXT_RST_Pin, GPIO_PIN_RESET);

  /*Configure GPIO pin : LCD_B0_Pin */
  GPIO_InitStruct.Pin = LCD_B0_Pin;
  GPIO_InitStruct.Mode = GPIO_MODE_AF_PP;
  GPIO_InitStruct.Pull = GPIO_NOPULL;
  GPIO_InitStruct.Speed = GPIO_SPEED_FREQ_LOW;
  GPIO_InitStruct.Alternate = GPIO_AF14_LTDC;
  HAL_GPIO_Init(LCD_B0_GPIO_Port, &GPIO_InitStruct);

  /*Configure GPIO pin : OTG_HS_OverCurrent_Pin */
  GPIO_InitStruct.Pin = OTG_HS_OverCurrent_Pin;
  GPIO_InitStruct.Mode = GPIO_MODE_INPUT;
  GPIO_InitStruct.Pull = GPIO_NOPULL;
  HAL_GPIO_Init(OTG_HS_OverCurrent_GPIO_Port, &GPIO_InitStruct);

  /*Configure GPIO pin : QSPI_D2_Pin */
  GPIO_InitStruct.Pin = QSPI_D2_Pin;
  GPIO_InitStruct.Mode = GPIO_MODE_AF_PP;
  GPIO_InitStruct.Pull = GPIO_NOPULL;
  GPIO_InitStruct.Speed = GPIO_SPEED_FREQ_VERY_HIGH;
  GPIO_InitStruct.Alternate = GPIO_AF9_QUADSPI;
  HAL_GPIO_Init(QSPI_D2_GPIO_Port, &GPIO_InitStruct);

  /*Configure GPIO pins : RMII_TXD1_Pin RMII_TXD0_Pin RMII_TX_EN_Pin */
  GPIO_InitStruct.Pin = RMII_TXD1_Pin|RMII_TXD0_Pin|RMII_TX_EN_Pin;
  GPIO_InitStruct.Mode = GPIO_MODE_AF_PP;
  GPIO_InitStruct.Pull = GPIO_NOPULL;
  GPIO_InitStruct.Speed = GPIO_SPEED_FREQ_VERY_HIGH;
  GPIO_InitStruct.Alternate = GPIO_AF11_ETH;
  HAL_GPIO_Init(GPIOG, &GPIO_InitStruct);

  /*Configure GPIO pins : FMC_NBL1_Pin FMC_NBL0_Pin FMC_D5_Pin FMC_D6_Pin
                           FMC_D8_Pin FMC_D11_Pin FMC_D4_Pin FMC_D7_Pin
                           FMC_D9_Pin FMC_D12_Pin FMC_D10_Pin */
  GPIO_InitStruct.Pin = FMC_NBL1_Pin|FMC_NBL0_Pin|FMC_D5_Pin|FMC_D6_Pin
                          |FMC_D8_Pin|FMC_D11_Pin|FMC_D4_Pin|FMC_D7_Pin
                          |FMC_D9_Pin|FMC_D12_Pin|FMC_D10_Pin;
  GPIO_InitStruct.Mode = GPIO_MODE_AF_PP;
  GPIO_InitStruct.Pull = GPIO_NOPULL;
  GPIO_InitStruct.Speed = GPIO_SPEED_FREQ_VERY_HIGH;
  GPIO_InitStruct.Alternate = GPIO_AF12_FMC;
  HAL_GPIO_Init(GPIOE, &GPIO_InitStruct);

  /*Configure GPIO pins : ARDUINO_SCL_D15_Pin ARDUINO_SDA_D14_Pin */
  GPIO_InitStruct.Pin = ARDUINO_SCL_D15_Pin|ARDUINO_SDA_D14_Pin;
  GPIO_InitStruct.Mode = GPIO_MODE_AF_OD;
  GPIO_InitStruct.Pull = GPIO_PULLUP;
  GPIO_InitStruct.Speed = GPIO_SPEED_FREQ_LOW;
  GPIO_InitStruct.Alternate = GPIO_AF4_I2C1;
  HAL_GPIO_Init(GPIOB, &GPIO_InitStruct);

  /*Configure GPIO pins : ULPI_D7_Pin ULPI_D6_Pin ULPI_D5_Pin ULPI_D3_Pin
                           ULPI_D2_Pin ULPI_D1_Pin ULPI_D4_Pin */
  GPIO_InitStruct.Pin = ULPI_D7_Pin|ULPI_D6_Pin|ULPI_D5_Pin|ULPI_D3_Pin
                          |ULPI_D2_Pin|ULPI_D1_Pin|ULPI_D4_Pin;
  GPIO_InitStruct.Mode = GPIO_MODE_AF_PP;
  GPIO_InitStruct.Pull = GPIO_NOPULL;
  GPIO_InitStruct.Speed = GPIO_SPEED_FREQ_VERY_HIGH;
  GPIO_InitStruct.Alternate = GPIO_AF10_OTG_HS;
  HAL_GPIO_Init(GPIOB, &GPIO_InitStruct);

  /*Configure GPIO pin : ARDUINO_PWM_D3_Pin */
  GPIO_InitStruct.Pin = ARDUINO_PWM_D3_Pin;
  GPIO_InitStruct.Mode = GPIO_MODE_AF_PP;
  GPIO_InitStruct.Pull = GPIO_NOPULL;
  GPIO_InitStruct.Speed = GPIO_SPEED_FREQ_LOW;
  GPIO_InitStruct.Alternate = GPIO_AF2_TIM3;
  HAL_GPIO_Init(ARDUINO_PWM_D3_GPIO_Port, &GPIO_InitStruct);

  /*Configure GPIO pin : SPDIF_RX0_Pin */
  GPIO_InitStruct.Pin = SPDIF_RX0_Pin;
  GPIO_InitStruct.Mode = GPIO_MODE_AF_PP;
  GPIO_InitStruct.Pull = GPIO_NOPULL;
  GPIO_InitStruct.Speed = GPIO_SPEED_FREQ_LOW;
  GPIO_InitStruct.Alternate = GPIO_AF8_SPDIFRX;
  HAL_GPIO_Init(SPDIF_RX0_GPIO_Port, &GPIO_InitStruct);

  /*Configure GPIO pins : SDMMC_CK_Pin SDMMC_D3_Pin SDMMC_D2_Pin PC9
                           PC8 */
  GPIO_InitStruct.Pin = SDMMC_CK_Pin|SDMMC_D3_Pin|SDMMC_D2_Pin|GPIO_PIN_9
                          |GPIO_PIN_8;
  GPIO_InitStruct.Mode = GPIO_MODE_AF_PP;
  GPIO_InitStruct.Pull = GPIO_NOPULL;
  GPIO_InitStruct.Speed = GPIO_SPEED_FREQ_VERY_HIGH;
  GPIO_InitStruct.Alternate = GPIO_AF12_SDMMC1;
  HAL_GPIO_Init(GPIOC, &GPIO_InitStruct);

  /*Configure GPIO pin : ARDUINO_PWM_D9_Pin */
  GPIO_InitStruct.Pin = ARDUINO_PWM_D9_Pin;
  GPIO_InitStruct.Mode = GPIO_MODE_AF_PP;
  GPIO_InitStruct.Pull = GPIO_NOPULL;
  GPIO_InitStruct.Speed = GPIO_SPEED_FREQ_LOW;
  GPIO_InitStruct.Alternate = GPIO_AF1_TIM2;
  HAL_GPIO_Init(ARDUINO_PWM_D9_GPIO_Port, &GPIO_InitStruct);

  /*Configure GPIO pins : DCMI_D6_Pin DCMI_D7_Pin */
  GPIO_InitStruct.Pin = DCMI_D6_Pin|DCMI_D7_Pin;
  GPIO_InitStruct.Mode = GPIO_MODE_AF_PP;
  GPIO_InitStruct.Pull = GPIO_NOPULL;
  GPIO_InitStruct.Speed = GPIO_SPEED_FREQ_LOW;
  GPIO_InitStruct.Alternate = GPIO_AF13_DCMI;
  HAL_GPIO_Init(GPIOE, &GPIO_InitStruct);

  /*Configure GPIO pin : VCP_RX_Pin */
  GPIO_InitStruct.Pin = VCP_RX_Pin;
  GPIO_InitStruct.Mode = GPIO_MODE_AF_PP;
  GPIO_InitStruct.Pull = GPIO_NOPULL;
  GPIO_InitStruct.Speed = GPIO_SPEED_FREQ_LOW;
  GPIO_InitStruct.Alternate = GPIO_AF7_USART1;
  HAL_GPIO_Init(VCP_RX_GPIO_Port, &GPIO_InitStruct);

  /*Configure GPIO pin : QSPI_NCS_Pin */
  GPIO_InitStruct.Pin = QSPI_NCS_Pin;
  GPIO_InitStruct.Mode = GPIO_MODE_AF_PP;
  GPIO_InitStruct.Pull = GPIO_NOPULL;
  GPIO_InitStruct.Speed = GPIO_SPEED_FREQ_VERY_HIGH;
  GPIO_InitStruct.Alternate = GPIO_AF10_QUADSPI;
  HAL_GPIO_Init(QSPI_NCS_GPIO_Port, &GPIO_InitStruct);

  /*Configure GPIO pins : FMC_SDNCAS_Pin FMC_SDCLK_Pin FMC_A11_Pin FMC_A10_Pin
                           FMC_BA1_Pin FMC_BA0_Pin */
  GPIO_InitStruct.Pin = FMC_SDNCAS_Pin|FMC_SDCLK_Pin|FMC_A11_Pin|FMC_A10_Pin
                          |FMC_BA1_Pin|FMC_BA0_Pin;
  GPIO_InitStruct.Mode = GPIO_MODE_AF_PP;
  GPIO_InitStruct.Pull = GPIO_NOPULL;
  GPIO_InitStruct.Speed = GPIO_SPEED_FREQ_VERY_HIGH;
  GPIO_InitStruct.Alternate = GPIO_AF12_FMC;
  HAL_GPIO_Init(GPIOG, &GPIO_InitStruct);

  /*Configure GPIO pins : LCD_B1_Pin LCD_B2_Pin LCD_B3_Pin LCD_G4_Pin
                           LCD_G1_Pin LCD_G3_Pin LCD_G0_Pin LCD_G2_Pin
                           LCD_R7_Pin LCD_R5_Pin LCD_R6_Pin LCD_R4_Pin
                           LCD_R3_Pin LCD_R1_Pin LCD_R2_Pin */
  GPIO_InitStruct.Pin = LCD_B1_Pin|LCD_B2_Pin|LCD_B3_Pin|LCD_G4_Pin
                          |LCD_G1_Pin|LCD_G3_Pin|LCD_G0_Pin|LCD_G2_Pin
                          |LCD_R7_Pin|LCD_R5_Pin|LCD_R6_Pin|LCD_R4_Pin
                          |LCD_R3_Pin|LCD_R1_Pin|LCD_R2_Pin;
  GPIO_InitStruct.Mode = GPIO_MODE_AF_PP;
  GPIO_InitStruct.Pull = GPIO_NOPULL;
  GPIO_InitStruct.Speed = GPIO_SPEED_FREQ_LOW;
  GPIO_InitStruct.Alternate = GPIO_AF14_LTDC;
  HAL_GPIO_Init(GPIOJ, &GPIO_InitStruct);

  /*Configure GPIO pin : OTG_FS_VBUS_Pin */
  GPIO_InitStruct.Pin = OTG_FS_VBUS_Pin;
  GPIO_InitStruct.Mode = GPIO_MODE_INPUT;
  GPIO_InitStruct.Pull = GPIO_NOPULL;
  HAL_GPIO_Init(OTG_FS_VBUS_GPIO_Port, &GPIO_InitStruct);

  /*Configure GPIO pin : Audio_INT_Pin */
  /*
  GPIO_InitStruct.Pin = Audio_INT_Pin;
  GPIO_InitStruct.Mode = GPIO_MODE_EVT_RISING;
  GPIO_InitStruct.Pull = GPIO_NOPULL;
  HAL_GPIO_Init(Audio_INT_GPIO_Port, &GPIO_InitStruct);
*/
  /*Configure GPIO pins : FMC_D2_Pin FMC_D3_Pin FMC_D1_Pin FMC_D15_Pin
                           FMC_D0_Pin FMC_D14_Pin FMC_D13_Pin */
  GPIO_InitStruct.Pin = FMC_D2_Pin|FMC_D3_Pin|FMC_D1_Pin|FMC_D15_Pin
                          |FMC_D0_Pin|FMC_D14_Pin|FMC_D13_Pin;
  GPIO_InitStruct.Mode = GPIO_MODE_AF_PP;
  GPIO_InitStruct.Pull = GPIO_NOPULL;
  GPIO_InitStruct.Speed = GPIO_SPEED_FREQ_VERY_HIGH;
  GPIO_InitStruct.Alternate = GPIO_AF12_FMC;
  HAL_GPIO_Init(GPIOD, &GPIO_InitStruct);

  /*Configure GPIO pins : OTG_FS_P_Pin OTG_FS_N_Pin OTG_FS_ID_Pin */
  GPIO_InitStruct.Pin = OTG_FS_P_Pin|OTG_FS_N_Pin|OTG_FS_ID_Pin;
  GPIO_InitStruct.Mode = GPIO_MODE_AF_PP;
  GPIO_InitStruct.Pull = GPIO_NOPULL;
  GPIO_InitStruct.Speed = GPIO_SPEED_FREQ_VERY_HIGH;
  GPIO_InitStruct.Alternate = GPIO_AF10_OTG_FS;
  HAL_GPIO_Init(GPIOA, &GPIO_InitStruct);

  /*Configure GPIO pins : SAI2_MCLKA_Pin SAI2_SCKA_Pin SAI2_FSA_Pin SAI2_SDA_Pin */
  GPIO_InitStruct.Pin = SAI2_MCLKA_Pin|SAI2_SCKA_Pin|SAI2_FSA_Pin|SAI2_SDA_Pin;
  GPIO_InitStruct.Mode = GPIO_MODE_AF_PP;
  GPIO_InitStruct.Pull = GPIO_NOPULL;
  GPIO_InitStruct.Speed = GPIO_SPEED_FREQ_LOW;
  GPIO_InitStruct.Alternate = GPIO_AF10_SAI2;
  HAL_GPIO_Init(GPIOI, &GPIO_InitStruct);

  /*Configure GPIO pins : LCD_DE_Pin LCD_B7_Pin LCD_B6_Pin LCD_B5_Pin
                           LCD_G6_Pin LCD_G7_Pin LCD_G5_Pin */
  GPIO_InitStruct.Pin = LCD_DE_Pin|LCD_B7_Pin|LCD_B6_Pin|LCD_B5_Pin
                          |LCD_G6_Pin|LCD_G7_Pin|LCD_G5_Pin;
  GPIO_InitStruct.Mode = GPIO_MODE_AF_PP;
  GPIO_InitStruct.Pull = GPIO_NOPULL;
  GPIO_InitStruct.Speed = GPIO_SPEED_FREQ_LOW;
  GPIO_InitStruct.Alternate = GPIO_AF14_LTDC;
  HAL_GPIO_Init(GPIOK, &GPIO_InitStruct);

  /*Configure GPIO pin : LCD_B4_Pin */
  GPIO_InitStruct.Pin = LCD_B4_Pin;
  GPIO_InitStruct.Mode = GPIO_MODE_AF_PP;
  GPIO_InitStruct.Pull = GPIO_NOPULL;
  GPIO_InitStruct.Speed = GPIO_SPEED_FREQ_LOW;
  GPIO_InitStruct.Alternate = GPIO_AF9_LTDC;
  HAL_GPIO_Init(LCD_B4_GPIO_Port, &GPIO_InitStruct);

  /*Configure GPIO pin : SAI2_SDB_Pin */
  GPIO_InitStruct.Pin = SAI2_SDB_Pin;
  GPIO_InitStruct.Mode = GPIO_MODE_AF_PP;
  GPIO_InitStruct.Pull = GPIO_NOPULL;
  GPIO_InitStruct.Speed = GPIO_SPEED_FREQ_LOW;
  GPIO_InitStruct.Alternate = GPIO_AF10_SAI2;
  HAL_GPIO_Init(SAI2_SDB_GPIO_Port, &GPIO_InitStruct);

  /*Configure GPIO pin : OTG_FS_PowerSwitchOn_Pin */
  GPIO_InitStruct.Pin = OTG_FS_PowerSwitchOn_Pin;
  GPIO_InitStruct.Mode = GPIO_MODE_OUTPUT_PP;
  GPIO_InitStruct.Pull = GPIO_NOPULL;
  GPIO_InitStruct.Speed = GPIO_SPEED_FREQ_LOW;
  HAL_GPIO_Init(OTG_FS_PowerSwitchOn_GPIO_Port, &GPIO_InitStruct);

  /*Configure GPIO pin : DCMI_D5_Pin */
  GPIO_InitStruct.Pin = DCMI_D5_Pin;
  GPIO_InitStruct.Mode = GPIO_MODE_AF_PP;
  GPIO_InitStruct.Pull = GPIO_NOPULL;
  GPIO_InitStruct.Speed = GPIO_SPEED_FREQ_LOW;
  GPIO_InitStruct.Alternate = GPIO_AF13_DCMI;
  HAL_GPIO_Init(DCMI_D5_GPIO_Port, &GPIO_InitStruct);

  /*Configure GPIO pins : ARDUINO_D7_Pin ARDUINO_D8_Pin ARDUINO_D13_Pin LCD_DISP_Pin */
  GPIO_InitStruct.Pin = ARDUINO_D7_Pin|ARDUINO_D8_Pin|LCD_DISP_Pin;
  GPIO_InitStruct.Mode = GPIO_MODE_OUTPUT_PP;
  GPIO_InitStruct.Pull = GPIO_NOPULL;
  GPIO_InitStruct.Speed = GPIO_SPEED_FREQ_LOW;
  HAL_GPIO_Init(GPIOI, &GPIO_InitStruct);

  /*Configure GPIO pin : uSD_Detect_Pin */
  GPIO_InitStruct.Pin = uSD_Detect_Pin;
  GPIO_InitStruct.Mode = GPIO_MODE_INPUT;
  GPIO_InitStruct.Pull = GPIO_NOPULL;
  HAL_GPIO_Init(uSD_Detect_GPIO_Port, &GPIO_InitStruct);

  /*Configure GPIO pins : FMC_A0_Pin FMC_A1_Pin FMC_A2_Pin FMC_A3_Pin
                           FMC_A4_Pin FMC_A5_Pin FMC_A6_Pin FMC_A9_Pin
                           FMC_A7_Pin FMC_A8_Pin FMC_SDNRAS_Pin */
  GPIO_InitStruct.Pin = FMC_A0_Pin|FMC_A1_Pin|FMC_A2_Pin|FMC_A3_Pin
                          |FMC_A4_Pin|FMC_A5_Pin|FMC_A6_Pin|FMC_A9_Pin
                          |FMC_A7_Pin|FMC_A8_Pin|FMC_SDNRAS_Pin;
  GPIO_InitStruct.Mode = GPIO_MODE_AF_PP;
  GPIO_InitStruct.Pull = GPIO_NOPULL;
  GPIO_InitStruct.Speed = GPIO_SPEED_FREQ_VERY_HIGH;
  GPIO_InitStruct.Alternate = GPIO_AF12_FMC;
  HAL_GPIO_Init(GPIOF, &GPIO_InitStruct);

  /*Configure GPIO pins : LCD_HSYNC_Pin LCD_VSYNC_Pin LCD_R0_Pin LCD_CLK_Pin */
  GPIO_InitStruct.Pin = LCD_HSYNC_Pin|LCD_VSYNC_Pin|LCD_R0_Pin|LCD_CLK_Pin;
  GPIO_InitStruct.Mode = GPIO_MODE_AF_PP;
  GPIO_InitStruct.Pull = GPIO_NOPULL;
  GPIO_InitStruct.Speed = GPIO_SPEED_FREQ_LOW;
  GPIO_InitStruct.Alternate = GPIO_AF14_LTDC;
  HAL_GPIO_Init(GPIOI, &GPIO_InitStruct);

  /*Configure GPIO pin : LCD_BL_CTRL_Pin */
  GPIO_InitStruct.Pin = LCD_BL_CTRL_Pin;
  GPIO_InitStruct.Mode = GPIO_MODE_OUTPUT_PP;
  GPIO_InitStruct.Pull = GPIO_NOPULL;
  GPIO_InitStruct.Speed = GPIO_SPEED_FREQ_LOW;
  HAL_GPIO_Init(LCD_BL_CTRL_GPIO_Port, &GPIO_InitStruct);

  /*Configure GPIO pin : DCMI_VSYNC_Pin */
  GPIO_InitStruct.Pin = DCMI_VSYNC_Pin;
  GPIO_InitStruct.Mode = GPIO_MODE_AF_PP;
  GPIO_InitStruct.Pull = GPIO_NOPULL;
  GPIO_InitStruct.Speed = GPIO_SPEED_FREQ_LOW;
  GPIO_InitStruct.Alternate = GPIO_AF13_DCMI;
  HAL_GPIO_Init(DCMI_VSYNC_GPIO_Port, &GPIO_InitStruct);

  /*Configure GPIO pin : OTG_FS_OverCurrent_Pin */
  GPIO_InitStruct.Pin = OTG_FS_OverCurrent_Pin;
  GPIO_InitStruct.Mode = GPIO_MODE_INPUT;
  GPIO_InitStruct.Pull = GPIO_NOPULL;
  HAL_GPIO_Init(OTG_FS_OverCurrent_GPIO_Port, &GPIO_InitStruct);

  /*Configure GPIO pin : SDMMC_D0_Pin */
  GPIO_InitStruct.Pin = SDMMC_D0_Pin;
  GPIO_InitStruct.Mode = GPIO_MODE_AF_PP;
  GPIO_InitStruct.Pull = GPIO_NOPULL;
  GPIO_InitStruct.Speed = GPIO_SPEED_FREQ_VERY_HIGH;
  GPIO_InitStruct.Alternate = GPIO_AF12_SDMMC1;
  HAL_GPIO_Init(SDMMC_D0_GPIO_Port, &GPIO_InitStruct);

  /*Configure GPIO pins : TP3_Pin NC2_Pin */
  GPIO_InitStruct.Pin = TP3_Pin|NC2_Pin;
  GPIO_InitStruct.Mode = GPIO_MODE_INPUT;
  GPIO_InitStruct.Pull = GPIO_NOPULL;
  HAL_GPIO_Init(GPIOH, &GPIO_InitStruct);

    /*Configure GPIO pin : ARDUINO_SCK_D13_Pin */
  GPIO_InitStruct.Pin = ARDUINO_SCK_D13_Pin;
  GPIO_InitStruct.Mode = GPIO_MODE_AF_PP;
  GPIO_InitStruct.Pull = GPIO_NOPULL;
  GPIO_InitStruct.Speed = GPIO_SPEED_FREQ_LOW;
  GPIO_InitStruct.Alternate = GPIO_AF5_SPI2;
  HAL_GPIO_Init(ARDUINO_SCK_D13_GPIO_Port, &GPIO_InitStruct);

  /*Configure GPIO pin : DCMI_PWR_EN_Pin */
  GPIO_InitStruct.Pin = DCMI_PWR_EN_Pin;
  GPIO_InitStruct.Mode = GPIO_MODE_OUTPUT_PP;
  GPIO_InitStruct.Pull = GPIO_NOPULL;
  GPIO_InitStruct.Speed = GPIO_SPEED_FREQ_LOW;
  HAL_GPIO_Init(DCMI_PWR_EN_GPIO_Port, &GPIO_InitStruct);

  /*Configure GPIO pins : DCMI_D4_Pin DCMI_D3_Pin DCMI_D0_Pin DCMI_D2_Pin
                           DCMI_D1_Pin */
  GPIO_InitStruct.Pin = DCMI_D4_Pin|DCMI_D3_Pin|DCMI_D0_Pin|DCMI_D2_Pin
                          |DCMI_D1_Pin;
  GPIO_InitStruct.Mode = GPIO_MODE_AF_PP;
  GPIO_InitStruct.Pull = GPIO_NOPULL;
  GPIO_InitStruct.Speed = GPIO_SPEED_FREQ_LOW;
  GPIO_InitStruct.Alternate = GPIO_AF13_DCMI;
  HAL_GPIO_Init(GPIOH, &GPIO_InitStruct);

  /*Configure GPIO pin : ARDUINO_PWM_CS_D10_Pin */
  GPIO_InitStruct.Pin = ARDUINO_PWM_CS_D10_Pin;
  GPIO_InitStruct.Mode = GPIO_MODE_AF_PP;
  GPIO_InitStruct.Pull = GPIO_NOPULL;
  GPIO_InitStruct.Speed = GPIO_SPEED_FREQ_LOW;
  GPIO_InitStruct.Alternate = GPIO_AF2_TIM5;
  HAL_GPIO_Init(ARDUINO_PWM_CS_D10_GPIO_Port, &GPIO_InitStruct);

    /*Configure GPIO pin : VCP_TX_Pin */
  GPIO_InitStruct.Pin = VCP_TX_Pin;
  GPIO_InitStruct.Mode = GPIO_MODE_AF_PP;
  GPIO_InitStruct.Pull = GPIO_NOPULL;
  GPIO_InitStruct.Speed = GPIO_SPEED_FREQ_LOW;
  GPIO_InitStruct.Alternate = GPIO_AF7_USART1;
  HAL_GPIO_Init(VCP_TX_GPIO_Port, &GPIO_InitStruct);

  /*Configure GPIO pin : B_USER_Pin */
  GPIO_InitStruct.Pin = B_USER_Pin;
  GPIO_InitStruct.Mode = GPIO_MODE_IT_RISING;
  GPIO_InitStruct.Pull = GPIO_NOPULL;
  HAL_GPIO_Init(B_USER_GPIO_Port, &GPIO_InitStruct);

  /*Configure GPIO pin : ARDUINO_PWM_D5_Pin */
  GPIO_InitStruct.Pin = ARDUINO_PWM_D5_Pin;
  GPIO_InitStruct.Mode = GPIO_MODE_AF_PP;
  GPIO_InitStruct.Pull = GPIO_NOPULL;
  GPIO_InitStruct.Speed = GPIO_SPEED_FREQ_LOW;
  GPIO_InitStruct.Alternate = GPIO_AF1_TIM1;
  HAL_GPIO_Init(ARDUINO_PWM_D5_GPIO_Port, &GPIO_InitStruct);

  /*Configure GPIO pin : LCD_INT_Pin */
  GPIO_InitStruct.Pin = LCD_INT_Pin;
  GPIO_InitStruct.Mode = GPIO_MODE_EVT_RISING;
  GPIO_InitStruct.Pull = GPIO_NOPULL;
  HAL_GPIO_Init(LCD_INT_GPIO_Port, &GPIO_InitStruct);

  /*Configure GPIO pins : ARDUINO_RX_D0_Pin ARDUINO_TX_D1_Pin */
  GPIO_InitStruct.Pin = ARDUINO_RX_D0_Pin|ARDUINO_TX_D1_Pin;
  GPIO_InitStruct.Mode = GPIO_MODE_AF_PP;
  GPIO_InitStruct.Pull = GPIO_NOPULL;
  GPIO_InitStruct.Speed = GPIO_SPEED_FREQ_VERY_HIGH;
  GPIO_InitStruct.Alternate = GPIO_AF8_USART6;
  HAL_GPIO_Init(GPIOC, &GPIO_InitStruct);

  /*Configure GPIO pin : ULPI_NXT_Pin */
  GPIO_InitStruct.Pin = ULPI_NXT_Pin;
  GPIO_InitStruct.Mode = GPIO_MODE_AF_PP;
  GPIO_InitStruct.Pull = GPIO_NOPULL;
  GPIO_InitStruct.Speed = GPIO_SPEED_FREQ_VERY_HIGH;
  GPIO_InitStruct.Alternate = GPIO_AF10_OTG_HS;
  HAL_GPIO_Init(ULPI_NXT_GPIO_Port, &GPIO_InitStruct);

  /*Configure GPIO pins : FMC_SDNME_Pin FMC_SDNE0_Pin */
  GPIO_InitStruct.Pin = FMC_SDNME_Pin|FMC_SDNE0_Pin;
  GPIO_InitStruct.Mode = GPIO_MODE_AF_PP;
  GPIO_InitStruct.Pull = GPIO_NOPULL;
  GPIO_InitStruct.Speed = GPIO_SPEED_FREQ_VERY_HIGH;
  GPIO_InitStruct.Alternate = GPIO_AF12_FMC;
  HAL_GPIO_Init(GPIOH, &GPIO_InitStruct);

  /*Configure GPIO pins : ARDUINO_D4_Pin ARDUINO_D2_Pin EXT_RST_Pin */
  GPIO_InitStruct.Pin = ARDUINO_D4_Pin|EXT_RST_Pin;
  GPIO_InitStruct.Mode = GPIO_MODE_OUTPUT_PP;
  GPIO_InitStruct.Pull = GPIO_NOPULL;
  GPIO_InitStruct.Speed = GPIO_SPEED_FREQ_LOW;
  HAL_GPIO_Init(GPIOG, &GPIO_InitStruct);

  /*Configure GPIO pins : ARDUINO_A4_Pin ARDUINO_A5_Pin ARDUINO_A1_Pin ARDUINO_A2_Pin
                           ARDUINO_A3_Pin */
  GPIO_InitStruct.Pin = ARDUINO_A4_Pin|ARDUINO_A5_Pin|ARDUINO_A1_Pin|ARDUINO_A2_Pin
                          |ARDUINO_A3_Pin;
  GPIO_InitStruct.Mode = GPIO_MODE_ANALOG;
  GPIO_InitStruct.Pull = GPIO_NOPULL;
  HAL_GPIO_Init(GPIOF, &GPIO_InitStruct);

  /*Configure GPIO pin : FMC_SDCKE0_Pin */
  GPIO_InitStruct.Pin = FMC_SDCKE0_Pin;
  GPIO_InitStruct.Mode = GPIO_MODE_AF_PP;
  GPIO_InitStruct.Pull = GPIO_NOPULL;
  GPIO_InitStruct.Speed = GPIO_SPEED_FREQ_VERY_HIGH;
  GPIO_InitStruct.Alternate = GPIO_AF12_FMC;
  HAL_GPIO_Init(FMC_SDCKE0_GPIO_Port, &GPIO_InitStruct);

  /*Configure GPIO pins : ULPI_STP_Pin ULPI_DIR_Pin */
  GPIO_InitStruct.Pin = ULPI_STP_Pin|ULPI_DIR_Pin;
  GPIO_InitStruct.Mode = GPIO_MODE_AF_PP;
  GPIO_InitStruct.Pull = GPIO_NOPULL;
  GPIO_InitStruct.Speed = GPIO_SPEED_FREQ_VERY_HIGH;
  GPIO_InitStruct.Alternate = GPIO_AF10_OTG_HS;
  HAL_GPIO_Init(GPIOC, &GPIO_InitStruct);

  /*Configure GPIO pins : RMII_MDC_Pin RMII_RXD0_Pin RMII_RXD1_Pin */
  GPIO_InitStruct.Pin = RMII_MDC_Pin|RMII_RXD0_Pin|RMII_RXD1_Pin;
  GPIO_InitStruct.Mode = GPIO_MODE_AF_PP;
  GPIO_InitStruct.Pull = GPIO_NOPULL;
  GPIO_InitStruct.Speed = GPIO_SPEED_FREQ_VERY_HIGH;
  GPIO_InitStruct.Alternate = GPIO_AF11_ETH;
  HAL_GPIO_Init(GPIOC, &GPIO_InitStruct);

  /*Configure GPIO pin : PB2 */
  GPIO_InitStruct.Pin = GPIO_PIN_2;
  GPIO_InitStruct.Mode = GPIO_MODE_AF_PP;
  GPIO_InitStruct.Pull = GPIO_NOPULL;
  GPIO_InitStruct.Speed = GPIO_SPEED_FREQ_VERY_HIGH;
  GPIO_InitStruct.Alternate = GPIO_AF9_QUADSPI;
  HAL_GPIO_Init(GPIOB, &GPIO_InitStruct);

  /*Configure GPIO pins : QSPI_D1_Pin QSPI_D3_Pin QSPI_D0_Pin */
  GPIO_InitStruct.Pin = QSPI_D1_Pin|QSPI_D3_Pin|QSPI_D0_Pin;
  GPIO_InitStruct.Mode = GPIO_MODE_AF_PP;
  GPIO_InitStruct.Pull = GPIO_NOPULL;
  GPIO_InitStruct.Speed = GPIO_SPEED_FREQ_VERY_HIGH;
  GPIO_InitStruct.Alternate = GPIO_AF9_QUADSPI;
  HAL_GPIO_Init(GPIOD, &GPIO_InitStruct);

  /*Configure GPIO pin : RMII_RXER_Pin */
  GPIO_InitStruct.Pin = RMII_RXER_Pin;
  GPIO_InitStruct.Mode = GPIO_MODE_INPUT;
  GPIO_InitStruct.Pull = GPIO_NOPULL;
  HAL_GPIO_Init(RMII_RXER_GPIO_Port, &GPIO_InitStruct);

  /*Configure GPIO pins : RMII_REF_CLK_Pin RMII_MDIO_Pin RMII_CRS_DV_Pin */
  GPIO_InitStruct.Pin = RMII_REF_CLK_Pin|RMII_MDIO_Pin|RMII_CRS_DV_Pin;
  GPIO_InitStruct.Mode = GPIO_MODE_AF_PP;
  GPIO_InitStruct.Pull = GPIO_NOPULL;
  GPIO_InitStruct.Speed = GPIO_SPEED_FREQ_VERY_HIGH;
  GPIO_InitStruct.Alternate = GPIO_AF11_ETH;
  HAL_GPIO_Init(GPIOA, &GPIO_InitStruct);

  /*Configure GPIO pin : ARDUINO_A0_Pin */
  GPIO_InitStruct.Pin = ARDUINO_A0_Pin;
  GPIO_InitStruct.Mode = GPIO_MODE_ANALOG;
  GPIO_InitStruct.Pull = GPIO_NOPULL;
  HAL_GPIO_Init(ARDUINO_A0_GPIO_Port, &GPIO_InitStruct);

  /*Configure GPIO pins : DCMI_HSYNC_Pin PA6 */
  GPIO_InitStruct.Pin = DCMI_HSYNC_Pin|GPIO_PIN_6;
  GPIO_InitStruct.Mode = GPIO_MODE_AF_PP;
  GPIO_InitStruct.Pull = GPIO_NOPULL;
  GPIO_InitStruct.Speed = GPIO_SPEED_FREQ_LOW;
  GPIO_InitStruct.Alternate = GPIO_AF13_DCMI;
  HAL_GPIO_Init(GPIOA, &GPIO_InitStruct);

  /*Configure GPIO pins : LCD_SCL_Pin LCD_SDA_Pin */
  GPIO_InitStruct.Pin = LCD_SCL_Pin|LCD_SDA_Pin;
  GPIO_InitStruct.Mode = GPIO_MODE_AF_OD;
  GPIO_InitStruct.Pull = GPIO_PULLUP;
  GPIO_InitStruct.Speed = GPIO_SPEED_FREQ_VERY_HIGH;
  GPIO_InitStruct.Alternate = GPIO_AF4_I2C3;
  HAL_GPIO_Init(GPIOH, &GPIO_InitStruct);

  /*Configure GPIO pins : ULPI_CLK_Pin ULPI_D0_Pin */
  GPIO_InitStruct.Pin = ULPI_CLK_Pin|ULPI_D0_Pin;
  GPIO_InitStruct.Mode = GPIO_MODE_AF_PP;
  GPIO_InitStruct.Pull = GPIO_NOPULL;
  GPIO_InitStruct.Speed = GPIO_SPEED_FREQ_VERY_HIGH;
  GPIO_InitStruct.Alternate = GPIO_AF10_OTG_HS;
  HAL_GPIO_Init(GPIOA, &GPIO_InitStruct);

  /*Configure GPIO pin : ARDUINO_PWM_D6_Pin */
  GPIO_InitStruct.Pin = ARDUINO_PWM_D6_Pin;
  GPIO_InitStruct.Mode = GPIO_MODE_AF_PP;
  GPIO_InitStruct.Pull = GPIO_NOPULL;
  GPIO_InitStruct.Speed = GPIO_SPEED_FREQ_LOW;
  GPIO_InitStruct.Alternate = GPIO_AF9_TIM12;
  HAL_GPIO_Init(ARDUINO_PWM_D6_GPIO_Port, &GPIO_InitStruct);

  /*Configure GPIO pins : ARDUINO_MISO_D12_Pin ARDUINO_MOSI_PWM_D11_Pin */
  GPIO_InitStruct.Pin = ARDUINO_MISO_D12_Pin|ARDUINO_MOSI_PWM_D11_Pin;
  GPIO_InitStruct.Mode = GPIO_MODE_AF_PP;
  GPIO_InitStruct.Pull = GPIO_NOPULL;
  GPIO_InitStruct.Speed = GPIO_SPEED_FREQ_LOW;
  GPIO_InitStruct.Alternate = GPIO_AF5_SPI2;
  HAL_GPIO_Init(GPIOB, &GPIO_InitStruct);

  HAL_NVIC_SetPriority(EXTI15_10_IRQn, 0, 0);
  HAL_NVIC_EnableIRQ(EXTI15_10_IRQn);

}

void _Error_Handler(char * file, int line)
{
  while(1)
  {
  }
}

/************************ (C) COPYRIGHT STMicroelectronics *****END OF FILE****/
